VERSION 5.7 ;
BUSBITCHARS "[]" ;
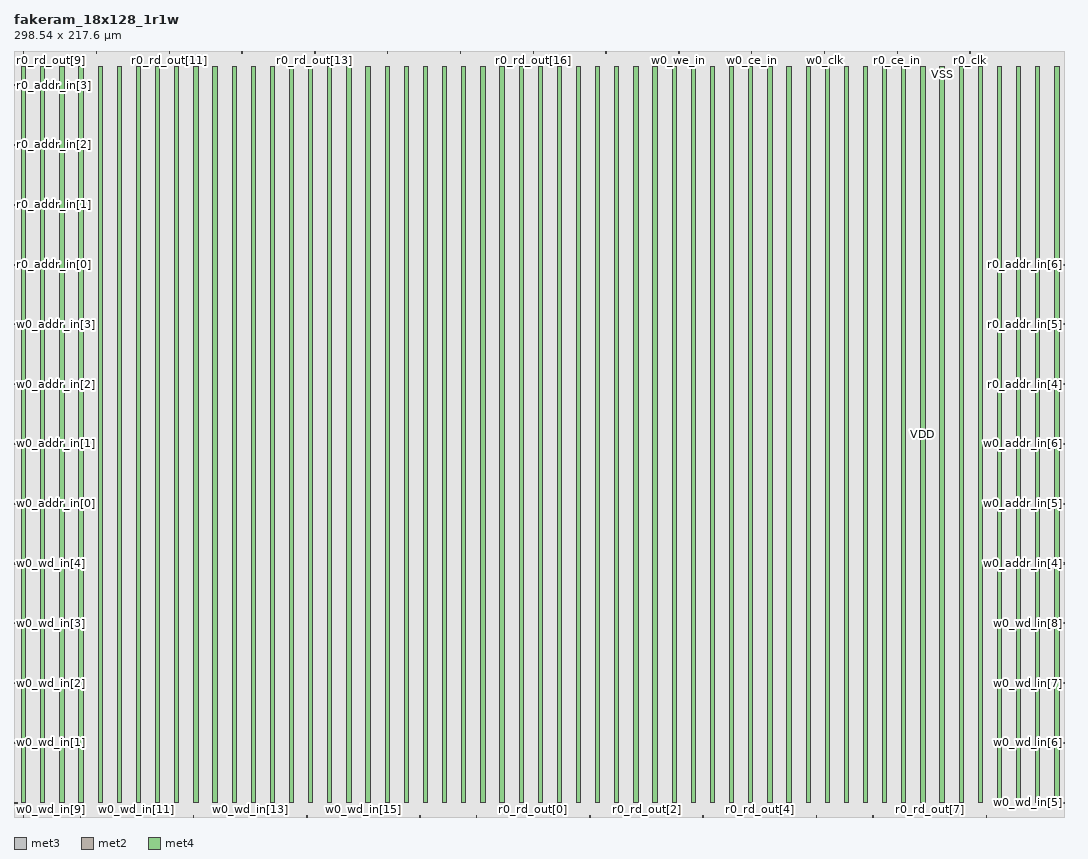
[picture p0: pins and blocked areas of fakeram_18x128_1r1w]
MACRO fakeram_18x128_1r1w
  FOREIGN fakeram_18x128_1r1w 0 0 ;
  SYMMETRY X Y R90 ;
  SIZE 298.540 BY 217.600 ;
  CLASS BLOCK ;
  PIN w0_wd_in[0]
    DIRECTION INPUT ;
    USE SIGNAL ;
    SHAPE ABUTMENT ;
    PORT
      LAYER met3 ;
      RECT 0.000 3.930 0.900 4.230 ;
    END
  END w0_wd_in[0]
  PIN w0_wd_in[1]
    DIRECTION INPUT ;
    USE SIGNAL ;
    SHAPE ABUTMENT ;
    PORT
      LAYER met3 ;
      RECT 0.000 20.930 0.900 21.230 ;
    END
  END w0_wd_in[1]
  PIN w0_wd_in[2]
    DIRECTION INPUT ;
    USE SIGNAL ;
    SHAPE ABUTMENT ;
    PORT
      LAYER met3 ;
      RECT 0.000 37.930 0.900 38.230 ;
    END
  END w0_wd_in[2]
  PIN w0_wd_in[3]
    DIRECTION INPUT ;
    USE SIGNAL ;
    SHAPE ABUTMENT ;
    PORT
      LAYER met3 ;
      RECT 0.000 54.930 0.900 55.230 ;
    END
  END w0_wd_in[3]
  PIN w0_wd_in[4]
    DIRECTION INPUT ;
    USE SIGNAL ;
    SHAPE ABUTMENT ;
    PORT
      LAYER met3 ;
      RECT 0.000 71.930 0.900 72.230 ;
    END
  END w0_wd_in[4]
  PIN w0_wd_in[5]
    DIRECTION INPUT ;
    USE SIGNAL ;
    SHAPE ABUTMENT ;
    PORT
      LAYER met3 ;
      RECT 297.640 3.930 298.540 4.230 ;
    END
  END w0_wd_in[5]
  PIN w0_wd_in[6]
    DIRECTION INPUT ;
    USE SIGNAL ;
    SHAPE ABUTMENT ;
    PORT
      LAYER met3 ;
      RECT 297.640 20.930 298.540 21.230 ;
    END
  END w0_wd_in[6]
  PIN w0_wd_in[7]
    DIRECTION INPUT ;
    USE SIGNAL ;
    SHAPE ABUTMENT ;
    PORT
      LAYER met3 ;
      RECT 297.640 37.930 298.540 38.230 ;
    END
  END w0_wd_in[7]
  PIN w0_wd_in[8]
    DIRECTION INPUT ;
    USE SIGNAL ;
    SHAPE ABUTMENT ;
    PORT
      LAYER met3 ;
      RECT 297.640 54.930 298.540 55.230 ;
    END
  END w0_wd_in[8]
  PIN w0_wd_in[9]
    DIRECTION INPUT ;
    USE SIGNAL ;
    SHAPE ABUTMENT ;
    PORT
      LAYER met2 ;
      RECT 2.690 0.000 2.830 0.420 ;
    END
  END w0_wd_in[9]
  PIN w0_wd_in[10]
    DIRECTION INPUT ;
    USE SIGNAL ;
    SHAPE ABUTMENT ;
    PORT
      LAYER met2 ;
      RECT 18.790 0.000 18.930 0.420 ;
    END
  END w0_wd_in[10]
  PIN w0_wd_in[11]
    DIRECTION INPUT ;
    USE SIGNAL ;
    SHAPE ABUTMENT ;
    PORT
      LAYER met2 ;
      RECT 34.890 0.000 35.030 0.420 ;
    END
  END w0_wd_in[11]
  PIN w0_wd_in[12]
    DIRECTION INPUT ;
    USE SIGNAL ;
    SHAPE ABUTMENT ;
    PORT
      LAYER met2 ;
      RECT 50.990 0.000 51.130 0.420 ;
    END
  END w0_wd_in[12]
  PIN w0_wd_in[13]
    DIRECTION INPUT ;
    USE SIGNAL ;
    SHAPE ABUTMENT ;
    PORT
      LAYER met2 ;
      RECT 67.090 0.000 67.230 0.420 ;
    END
  END w0_wd_in[13]
  PIN w0_wd_in[14]
    DIRECTION INPUT ;
    USE SIGNAL ;
    SHAPE ABUTMENT ;
    PORT
      LAYER met2 ;
      RECT 83.190 0.000 83.330 0.420 ;
    END
  END w0_wd_in[14]
  PIN w0_wd_in[15]
    DIRECTION INPUT ;
    USE SIGNAL ;
    SHAPE ABUTMENT ;
    PORT
      LAYER met2 ;
      RECT 99.290 0.000 99.430 0.420 ;
    END
  END w0_wd_in[15]
  PIN w0_wd_in[16]
    DIRECTION INPUT ;
    USE SIGNAL ;
    SHAPE ABUTMENT ;
    PORT
      LAYER met2 ;
      RECT 115.390 0.000 115.530 0.420 ;
    END
  END w0_wd_in[16]
  PIN w0_wd_in[17]
    DIRECTION INPUT ;
    USE SIGNAL ;
    SHAPE ABUTMENT ;
    PORT
      LAYER met2 ;
      RECT 131.490 0.000 131.630 0.420 ;
    END
  END w0_wd_in[17]
  PIN r0_rd_out[0]
    DIRECTION OUTPUT ;
    USE SIGNAL ;
    SHAPE ABUTMENT ;
    PORT
      LAYER met2 ;
      RECT 147.590 0.000 147.730 0.420 ;
    END
  END r0_rd_out[0]
  PIN r0_rd_out[1]
    DIRECTION OUTPUT ;
    USE SIGNAL ;
    SHAPE ABUTMENT ;
    PORT
      LAYER met2 ;
      RECT 163.690 0.000 163.830 0.420 ;
    END
  END r0_rd_out[1]
  PIN r0_rd_out[2]
    DIRECTION OUTPUT ;
    USE SIGNAL ;
    SHAPE ABUTMENT ;
    PORT
      LAYER met2 ;
      RECT 179.790 0.000 179.930 0.420 ;
    END
  END r0_rd_out[2]
  PIN r0_rd_out[3]
    DIRECTION OUTPUT ;
    USE SIGNAL ;
    SHAPE ABUTMENT ;
    PORT
      LAYER met2 ;
      RECT 195.890 0.000 196.030 0.420 ;
    END
  END r0_rd_out[3]
  PIN r0_rd_out[4]
    DIRECTION OUTPUT ;
    USE SIGNAL ;
    SHAPE ABUTMENT ;
    PORT
      LAYER met2 ;
      RECT 211.990 0.000 212.130 0.420 ;
    END
  END r0_rd_out[4]
  PIN r0_rd_out[5]
    DIRECTION OUTPUT ;
    USE SIGNAL ;
    SHAPE ABUTMENT ;
    PORT
      LAYER met2 ;
      RECT 228.090 0.000 228.230 0.420 ;
    END
  END r0_rd_out[5]
  PIN r0_rd_out[6]
    DIRECTION OUTPUT ;
    USE SIGNAL ;
    SHAPE ABUTMENT ;
    PORT
      LAYER met2 ;
      RECT 244.190 0.000 244.330 0.420 ;
    END
  END r0_rd_out[6]
  PIN r0_rd_out[7]
    DIRECTION OUTPUT ;
    USE SIGNAL ;
    SHAPE ABUTMENT ;
    PORT
      LAYER met2 ;
      RECT 260.290 0.000 260.430 0.420 ;
    END
  END r0_rd_out[7]
  PIN r0_rd_out[8]
    DIRECTION OUTPUT ;
    USE SIGNAL ;
    SHAPE ABUTMENT ;
    PORT
      LAYER met2 ;
      RECT 276.390 0.000 276.530 0.420 ;
    END
  END r0_rd_out[8]
  PIN r0_rd_out[9]
    DIRECTION OUTPUT ;
    USE SIGNAL ;
    SHAPE ABUTMENT ;
    PORT
      LAYER met2 ;
      RECT 2.690 217.180 2.830 217.600 ;
    END
  END r0_rd_out[9]
  PIN r0_rd_out[10]
    DIRECTION OUTPUT ;
    USE SIGNAL ;
    SHAPE ABUTMENT ;
    PORT
      LAYER met2 ;
      RECT 23.390 217.180 23.530 217.600 ;
    END
  END r0_rd_out[10]
  PIN r0_rd_out[11]
    DIRECTION OUTPUT ;
    USE SIGNAL ;
    SHAPE ABUTMENT ;
    PORT
      LAYER met2 ;
      RECT 44.090 217.180 44.230 217.600 ;
    END
  END r0_rd_out[11]
  PIN r0_rd_out[12]
    DIRECTION OUTPUT ;
    USE SIGNAL ;
    SHAPE ABUTMENT ;
    PORT
      LAYER met2 ;
      RECT 64.790 217.180 64.930 217.600 ;
    END
  END r0_rd_out[12]
  PIN r0_rd_out[13]
    DIRECTION OUTPUT ;
    USE SIGNAL ;
    SHAPE ABUTMENT ;
    PORT
      LAYER met2 ;
      RECT 85.490 217.180 85.630 217.600 ;
    END
  END r0_rd_out[13]
  PIN r0_rd_out[14]
    DIRECTION OUTPUT ;
    USE SIGNAL ;
    SHAPE ABUTMENT ;
    PORT
      LAYER met2 ;
      RECT 106.190 217.180 106.330 217.600 ;
    END
  END r0_rd_out[14]
  PIN r0_rd_out[15]
    DIRECTION OUTPUT ;
    USE SIGNAL ;
    SHAPE ABUTMENT ;
    PORT
      LAYER met2 ;
      RECT 126.890 217.180 127.030 217.600 ;
    END
  END r0_rd_out[15]
  PIN r0_rd_out[16]
    DIRECTION OUTPUT ;
    USE SIGNAL ;
    SHAPE ABUTMENT ;
    PORT
      LAYER met2 ;
      RECT 147.590 217.180 147.730 217.600 ;
    END
  END r0_rd_out[16]
  PIN r0_rd_out[17]
    DIRECTION OUTPUT ;
    USE SIGNAL ;
    SHAPE ABUTMENT ;
    PORT
      LAYER met2 ;
      RECT 168.290 217.180 168.430 217.600 ;
    END
  END r0_rd_out[17]
  PIN w0_addr_in[0]
    DIRECTION INPUT ;
    USE SIGNAL ;
    SHAPE ABUTMENT ;
    PORT
      LAYER met3 ;
      RECT 0.000 88.930 0.900 89.230 ;
    END
  END w0_addr_in[0]
  PIN w0_addr_in[1]
    DIRECTION INPUT ;
    USE SIGNAL ;
    SHAPE ABUTMENT ;
    PORT
      LAYER met3 ;
      RECT 0.000 105.930 0.900 106.230 ;
    END
  END w0_addr_in[1]
  PIN w0_addr_in[2]
    DIRECTION INPUT ;
    USE SIGNAL ;
    SHAPE ABUTMENT ;
    PORT
      LAYER met3 ;
      RECT 0.000 122.930 0.900 123.230 ;
    END
  END w0_addr_in[2]
  PIN w0_addr_in[3]
    DIRECTION INPUT ;
    USE SIGNAL ;
    SHAPE ABUTMENT ;
    PORT
      LAYER met3 ;
      RECT 0.000 139.930 0.900 140.230 ;
    END
  END w0_addr_in[3]
  PIN w0_addr_in[4]
    DIRECTION INPUT ;
    USE SIGNAL ;
    SHAPE ABUTMENT ;
    PORT
      LAYER met3 ;
      RECT 297.640 71.930 298.540 72.230 ;
    END
  END w0_addr_in[4]
  PIN w0_addr_in[5]
    DIRECTION INPUT ;
    USE SIGNAL ;
    SHAPE ABUTMENT ;
    PORT
      LAYER met3 ;
      RECT 297.640 88.930 298.540 89.230 ;
    END
  END w0_addr_in[5]
  PIN w0_addr_in[6]
    DIRECTION INPUT ;
    USE SIGNAL ;
    SHAPE ABUTMENT ;
    PORT
      LAYER met3 ;
      RECT 297.640 105.930 298.540 106.230 ;
    END
  END w0_addr_in[6]
  PIN r0_addr_in[0]
    DIRECTION INPUT ;
    USE SIGNAL ;
    SHAPE ABUTMENT ;
    PORT
      LAYER met3 ;
      RECT 0.000 156.930 0.900 157.230 ;
    END
  END r0_addr_in[0]
  PIN r0_addr_in[1]
    DIRECTION INPUT ;
    USE SIGNAL ;
    SHAPE ABUTMENT ;
    PORT
      LAYER met3 ;
      RECT 0.000 173.930 0.900 174.230 ;
    END
  END r0_addr_in[1]
  PIN r0_addr_in[2]
    DIRECTION INPUT ;
    USE SIGNAL ;
    SHAPE ABUTMENT ;
    PORT
      LAYER met3 ;
      RECT 0.000 190.930 0.900 191.230 ;
    END
  END r0_addr_in[2]
  PIN r0_addr_in[3]
    DIRECTION INPUT ;
    USE SIGNAL ;
    SHAPE ABUTMENT ;
    PORT
      LAYER met3 ;
      RECT 0.000 207.930 0.900 208.230 ;
    END
  END r0_addr_in[3]
  PIN r0_addr_in[4]
    DIRECTION INPUT ;
    USE SIGNAL ;
    SHAPE ABUTMENT ;
    PORT
      LAYER met3 ;
      RECT 297.640 122.930 298.540 123.230 ;
    END
  END r0_addr_in[4]
  PIN r0_addr_in[5]
    DIRECTION INPUT ;
    USE SIGNAL ;
    SHAPE ABUTMENT ;
    PORT
      LAYER met3 ;
      RECT 297.640 139.930 298.540 140.230 ;
    END
  END r0_addr_in[5]
  PIN r0_addr_in[6]
    DIRECTION INPUT ;
    USE SIGNAL ;
    SHAPE ABUTMENT ;
    PORT
      LAYER met3 ;
      RECT 297.640 156.930 298.540 157.230 ;
    END
  END r0_addr_in[6]
  PIN w0_we_in
    DIRECTION INPUT ;
    USE SIGNAL ;
    SHAPE ABUTMENT ;
    PORT
      LAYER met2 ;
      RECT 188.990 217.180 189.130 217.600 ;
    END
  END w0_we_in
  PIN w0_ce_in
    DIRECTION INPUT ;
    USE SIGNAL ;
    SHAPE ABUTMENT ;
    PORT
      LAYER met2 ;
      RECT 209.690 217.180 209.830 217.600 ;
    END
  END w0_ce_in
  PIN w0_clk
    DIRECTION INPUT ;
    USE SIGNAL ;
    SHAPE ABUTMENT ;
    PORT
      LAYER met2 ;
      RECT 230.390 217.180 230.530 217.600 ;
    END
  END w0_clk
  PIN r0_ce_in
    DIRECTION INPUT ;
    USE SIGNAL ;
    SHAPE ABUTMENT ;
    PORT
      LAYER met2 ;
      RECT 251.090 217.180 251.230 217.600 ;
    END
  END r0_ce_in
  PIN r0_clk
    DIRECTION INPUT ;
    USE SIGNAL ;
    SHAPE ABUTMENT ;
    PORT
      LAYER met2 ;
      RECT 271.790 217.180 271.930 217.600 ;
    END
  END r0_clk
  PIN VSS
    DIRECTION INOUT ;
    USE GROUND ;
    PORT
      LAYER met4 ;
      RECT 2.160 4.080 3.360 213.520 ;
      RECT 13.040 4.080 14.240 213.520 ;
      RECT 23.920 4.080 25.120 213.520 ;
      RECT 34.800 4.080 36.000 213.520 ;
      RECT 45.680 4.080 46.880 213.520 ;
      RECT 56.560 4.080 57.760 213.520 ;
      RECT 67.440 4.080 68.640 213.520 ;
      RECT 78.320 4.080 79.520 213.520 ;
      RECT 89.200 4.080 90.400 213.520 ;
      RECT 100.080 4.080 101.280 213.520 ;
      RECT 110.960 4.080 112.160 213.520 ;
      RECT 121.840 4.080 123.040 213.520 ;
      RECT 132.720 4.080 133.920 213.520 ;
      RECT 143.600 4.080 144.800 213.520 ;
      RECT 154.480 4.080 155.680 213.520 ;
      RECT 165.360 4.080 166.560 213.520 ;
      RECT 176.240 4.080 177.440 213.520 ;
      RECT 187.120 4.080 188.320 213.520 ;
      RECT 198.000 4.080 199.200 213.520 ;
      RECT 208.880 4.080 210.080 213.520 ;
      RECT 219.760 4.080 220.960 213.520 ;
      RECT 230.640 4.080 231.840 213.520 ;
      RECT 241.520 4.080 242.720 213.520 ;
      RECT 252.400 4.080 253.600 213.520 ;
      RECT 263.280 4.080 264.480 213.520 ;
      RECT 274.160 4.080 275.360 213.520 ;
      RECT 285.040 4.080 286.240 213.520 ;
      RECT 295.920 4.080 297.120 213.520 ;
    END
  END VSS
  PIN VDD
    DIRECTION INOUT ;
    USE POWER ;
    PORT
      LAYER met4 ;
      RECT 7.600 4.080 8.800 213.520 ;
      RECT 18.480 4.080 19.680 213.520 ;
      RECT 29.360 4.080 30.560 213.520 ;
      RECT 40.240 4.080 41.440 213.520 ;
      RECT 51.120 4.080 52.320 213.520 ;
      RECT 62.000 4.080 63.200 213.520 ;
      RECT 72.880 4.080 74.080 213.520 ;
      RECT 83.760 4.080 84.960 213.520 ;
      RECT 94.640 4.080 95.840 213.520 ;
      RECT 105.520 4.080 106.720 213.520 ;
      RECT 116.400 4.080 117.600 213.520 ;
      RECT 127.280 4.080 128.480 213.520 ;
      RECT 138.160 4.080 139.360 213.520 ;
      RECT 149.040 4.080 150.240 213.520 ;
      RECT 159.920 4.080 161.120 213.520 ;
      RECT 170.800 4.080 172.000 213.520 ;
      RECT 181.680 4.080 182.880 213.520 ;
      RECT 192.560 4.080 193.760 213.520 ;
      RECT 203.440 4.080 204.640 213.520 ;
      RECT 214.320 4.080 215.520 213.520 ;
      RECT 225.200 4.080 226.400 213.520 ;
      RECT 236.080 4.080 237.280 213.520 ;
      RECT 246.960 4.080 248.160 213.520 ;
      RECT 257.840 4.080 259.040 213.520 ;
      RECT 268.720 4.080 269.920 213.520 ;
      RECT 279.600 4.080 280.800 213.520 ;
      RECT 290.480 4.080 291.680 213.520 ;
    END
  END VDD
  OBS
    LAYER met1 ;
    RECT 0 0 298.540 217.600 ;
    LAYER met2 ;
    RECT 0 0 298.540 217.600 ;
    LAYER met3 ;
    RECT 0 0 298.540 217.600 ;
    LAYER met4 ;
    RECT 0 0 298.540 217.600 ;
  END
END fakeram_18x128_1r1w

END LIBRARY
